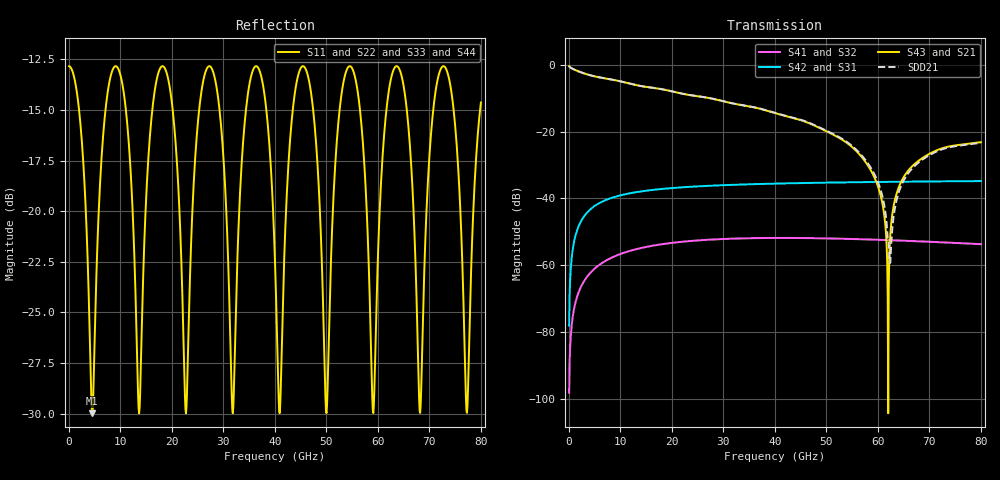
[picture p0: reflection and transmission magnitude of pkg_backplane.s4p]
! SYNTHESISED, NOT MEASURED. Generated by apps/s4p_gen.c.
! Physical model, not a capture of real hardware. Replace this
! file with a VNA sweep or a field-solver export when you have one;
! the reader in src/touchstone.c takes either without changes.
! Coupled lane pair, chained ports:
!  1 victim near  2 victim far  3 aggressor near  4 aggressor far
! S21 through, S23 FEXT, S11 return loss.
! insertion loss  14.0 dB at 50 GHz (Nyquist)
! skin / dielectric 1.0889 dB/sqrt(GHz) / 0.1260 dB/GHz
! flight time  420 ps end to end
! discontinuities  rho 0.13 and 0.10, 55 ps apart
!  -> echo at 11.0 UI after the cursor
! via stub  quarter-wave notch at 62 GHz
! FEXT  -38 dB at Nyquist, rising with frequency
#  GHZ  S  RI  R  50
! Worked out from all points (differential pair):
!   801 points, 50 MHz to 80 GHz, reference 50 ohm
!   strongest paths, dB at 50 MHz, 20.04 GHz, 40.02 GHz, 60.01 GHz, 80 GHz:
!     S43: -0.4, -7.9, -14.5, -36.4, -23.2
!     S21: -0.4, -7.9, -14.5, -36.4, -23.2
!     S42: -78.1, -36.9, -35.6, -35.1, -34.8
!     S31: -78.1, -36.9, -35.6, -35.1, -34.8
!     S41: -98.2, -53.3, -51.9, -52.4, -53.7
!     S32: -98.2, -53.3, -51.9, -52.4, -53.7
!   taken as a pair (ports 3,1 in; 4,2 out), SDD21 dB: -0.4, -7.9, -14.4, -35.1, -23.3
!   lowest |S11| = -30.0 dB at 4.547 GHz (marker M1), VSWR 1.07, Z = 53.3 + j0.0126 ohm
!   |S11| at or under -10 dB: start of sweep to end of sweep
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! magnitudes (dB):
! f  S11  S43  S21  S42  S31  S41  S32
! 50 MHz  -12.8  -0.4  -0.4  -78.1  -78.1  -98.2  -98.2
! 4.547 GHz  -30.0  -3.3  -3.3  -42.8  -42.8  -61.7  -61.7
! 53.22 GHz  -13.8  -22.6  -22.6  -35.2  -35.2  -52.1  -52.1
! 59.91 GHz  -23.0  -36.0  -36.0  -35.1  -35.1  -52.4  -52.4
! 62.01 GHz  -14.2  -104.4  -104.4  -35.1  -35.1  -52.5  -52.5
! 65.61 GHz  -15.0  -32.3  -32.3  -35.0  -35.0  -52.7  -52.7
! 80 GHz  -14.6  -23.2  -23.2  -34.8  -34.8  -53.7  -53.7
